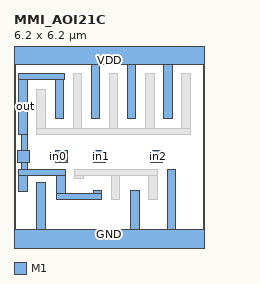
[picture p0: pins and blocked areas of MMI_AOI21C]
MACRO MMI_AOI21C
	CLASS CORE ;
	FOREIGN MMI_AOI21C 0 0 ;
	SIZE 6.2 BY 6.2 ;
	SYMMETRY X Y ;
	SITE CORE1 ;
	PIN out
		DIRECTION output ;
		USE SIGNAL ;
		PORT
			LAYER M1 ;
			RECT 0.15 5.315 1.64 5.505 ;
			LAYER M1 ;
			RECT 0.16 3.515 0.44 5.315 ;
			LAYER M1 ;
			RECT 1.34 4.045 1.62 5.315 ;
			LAYER M1 ;
			RECT 0.245 2.98 0.435 3.515 ;
			LAYER M1 ;
			RECT 0.12 2.6 0.5 2.98 ;
			LAYER M1 ;
			RECT 0.245 2.35 0.435 2.6 ;
			LAYER M1 ;
			RECT 0.16 2.16 1.68 2.35 ;
			LAYER M1 ;
			RECT 0.16 1.65 0.44 2.16 ;
			LAYER M1 ;
			RECT 1.4 1.585 1.68 2.16 ;
			LAYER M1 ;
			RECT 2.58 1.585 2.86 1.675 ;
			LAYER M1 ;
			RECT 1.4 1.39 2.86 1.585 ;
		END
		AntennaDiffArea 2.9568 ;
	END out
	PIN in1
		DIRECTION input ;
		USE SIGNAL ;
		PORT
			LAYER M1 ;
			RECT 2.6 2.93 2.98 2.98 ;
			LAYER M1 ;
			RECT 2.6 2.65 3.05 2.93 ;
			LAYER M1 ;
			RECT 2.6 2.6 2.98 2.65 ;
		END
		AntennaGateArea 1.386 ;
	END in1
	PIN GND
		DIRECTION inout ;
		USE GROUND ;
		PORT
			LAYER M1 ;
			RECT 0.75 0.42 1.03 1.93 ;
			LAYER M1 ;
			RECT 3.815 0.42 4.095 1.675 ;
			LAYER M1 ;
			RECT 4.995 0.42 5.275 2.35 ;
			LAYER M1 ;
			RECT 0 -0.42 6.2 0.42 ;
		END
	END GND
	PIN in2
		DIRECTION input ;
		USE SIGNAL ;
		PORT
			LAYER M1 ;
			RECT 4.46 2.93 4.84 2.98 ;
			LAYER M1 ;
			RECT 4.46 2.885 4.86 2.93 ;
			LAYER M1 ;
			RECT 4.46 2.695 4.915 2.885 ;
			LAYER M1 ;
			RECT 4.46 2.65 4.86 2.695 ;
			LAYER M1 ;
			RECT 4.46 2.6 4.84 2.65 ;
		END
		AntennaGateArea 1.386 ;
	END in2
	PIN VDD
		DIRECTION inout ;
		USE POWER ;
		PORT
			LAYER M1 ;
			RECT 0 5.78 6.2 6.62 ;
			LAYER M1 ;
			RECT 2.52 4.045 2.8 5.78 ;
			LAYER M1 ;
			RECT 3.7 4.045 3.98 5.78 ;
			LAYER M1 ;
			RECT 4.88 4.045 5.16 5.78 ;
		END
	END VDD
	PIN in0
		DIRECTION input ;
		USE SIGNAL ;
		PORT
			LAYER M1 ;
			RECT 1.36 2.93 1.74 2.98 ;
			LAYER M1 ;
			RECT 1.16 2.65 1.74 2.93 ;
			LAYER M1 ;
			RECT 1.36 2.6 1.74 2.65 ;
		END
		AntennaGateArea 1.15575 ;
	END in0
	OBS
		LAYER M1 ;
		RECT 0.75 3.71 1.03 4.965 ;
		LAYER M1 ;
		RECT 1.93 3.71 2.21 5.5 ;
		LAYER M1 ;
		RECT 3.11 3.71 3.39 5.5 ;
		LAYER M1 ;
		RECT 4.29 3.71 4.57 5.5 ;
		LAYER M1 ;
		RECT 5.47 3.71 5.75 5.5 ;
		LAYER M1 ;
		RECT 0.75 3.515 5.77 3.71 ;
		LAYER M1 ;
		RECT 1.99 2.16 4.685 2.35 ;
		LAYER M1 ;
		RECT 1.99 2.065 2.27 2.16 ;
		LAYER M1 ;
		RECT 3.17 1.395 3.45 2.16 ;
		LAYER M1 ;
		RECT 4.405 1.395 4.685 2.16 ;
	END
END MMI_AOI21C
